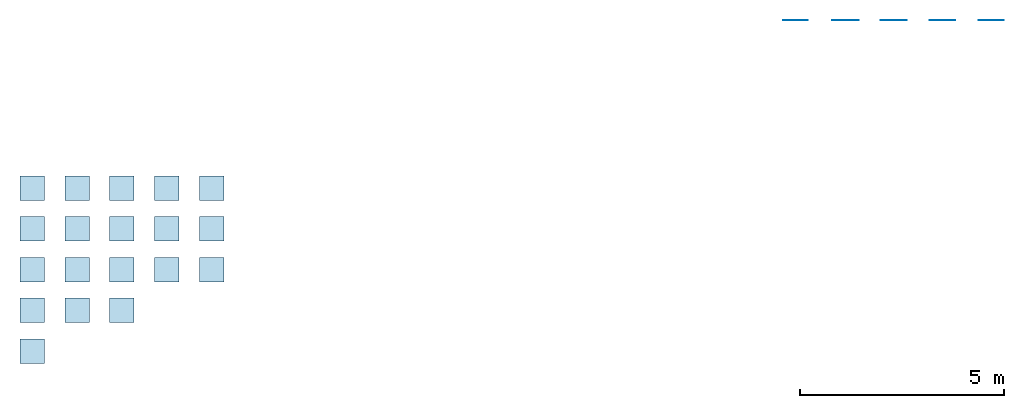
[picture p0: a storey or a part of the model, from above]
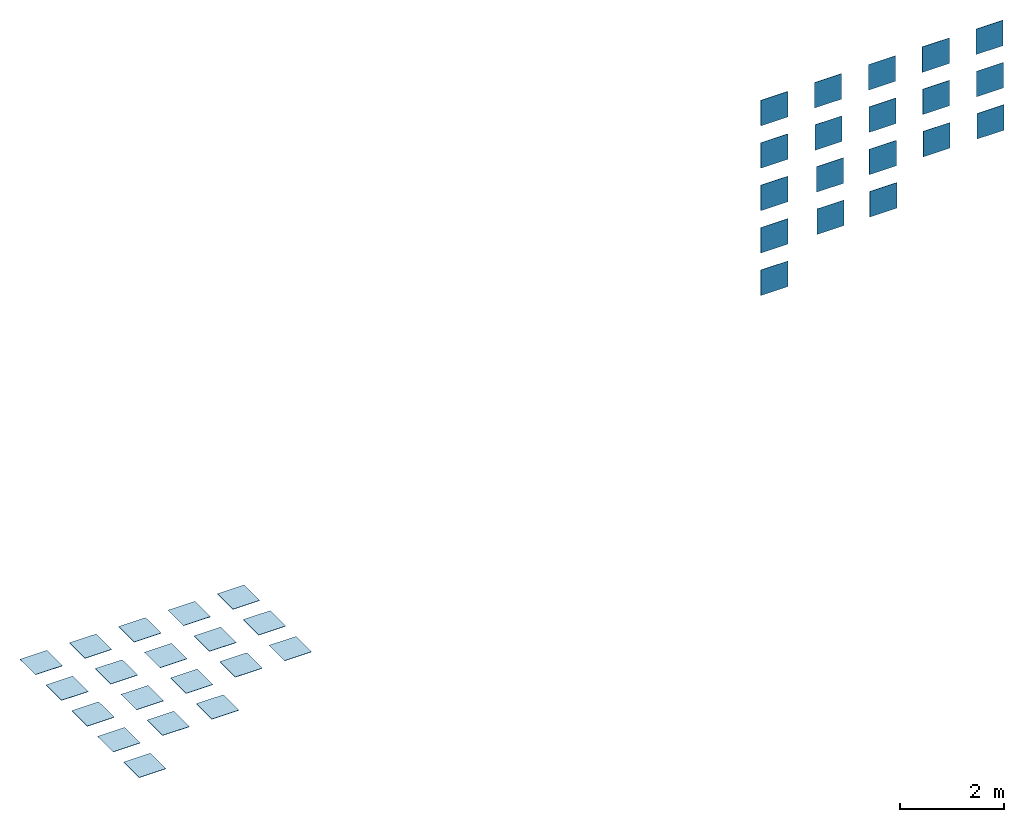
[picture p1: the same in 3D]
Properties of the parts of a building model (IFC2X3)

# File
Description: ViewDefinition [CoordinationView_V2.0]
File name: Número de proyecto
Time: 2017-10-19T12:50:17
Written by: The EXPRESS Data Manager Version 5.02.0100.07 : 28 Aug 2013
Made in: 20160225_1515(x64) - Exporter 17.0.416.0 - Alternate UI 17.12.14.0
Comment: STEP Physical File produced by: The EXPRESS Data Manager Version 5.02.0100.07 : 28 Aug 2013 * Module: EDMstepFileFactory/EDMstandAlone * Creation date: Thu Oct 19 12:50:17 2017 * Host: REVIT * Database: C:\Users\corte\AppData\Local\Temp\{6D7266B0-AC30-462C-87F8-137BDFE23D05}\ifc * Database version: 5507 * Database creation date: Thu Oct 19 12:50:14 2017 * Schema: IFC2X3 * Model: DataRepository.ifc * Model creation date: Thu Oct 19 12:50:14 2017 * Header model: DataRepository.ifc_HeaderModel * Header model creation date: Thu Oct 19 12:50:14 2017 * EDMuser: sdai-user * EDMgroup: sdai-group * License ID and type: 5605 : Permanent license. Expiry date: * EDMstepFileFactory options: 020000

# IfcProject, Número de proyecto
LongName: Nombre de proyecto; Phase: Estado de proyecto

# IfcSite, Default
RefLatitude: 40, 25, 0, 86975; RefLongitude: -3, -42, -1, -243858; RefElevation: 0 m

# IfcBuilding
Pset_BuildingCommon - NumberOfStoreys: 1

# IfcBuildingStorey, MAORI FLOOR TILES
LongName: MAORI FLOOR TILES; Elevation: 0 m

# IfcSlab: Suelo:VIVES BANNA 20x20, Suelo:VIVES BANNA 20x20:205106
In: MAORI FLOOR TILES
PredefinedType: FLOOR; Material: VIVES BANNA 20x20 0.008 m
Pset_SlabCommon - IsExternal: no; LoadBearing: yes; PitchAngle: 0 deg; Reference: VIVES BANNA 20x20; ThermalTransmittance: 187.5 kg/K/s3
Pset_ManufacturerTypeInformation - Manufacturer: VIVES Azulejos y Gres S.A.

# IfcSlab: Suelo:VIVES GOROKA CIELO 20x20, Suelo:VIVES GOROKA CIELO 20x20:204406
In: MAORI FLOOR TILES
PredefinedType: FLOOR; Material: VIVES GOROKA CIELO 20x20 0.008 m
Pset_SlabCommon - IsExternal: no; LoadBearing: yes; PitchAngle: 0 deg; Reference: VIVES GOROKA CIELO 20x20; ThermalTransmittance: 187.5 kg/K/s3
Pset_ManufacturerTypeInformation - Manufacturer: VIVES Azulejos y Gres S.A.

# IfcSlab: Suelo:VIVES GOROKA GRAFITO 20x20, Suelo:VIVES GOROKA GRAFITO 20x20:204430
In: MAORI FLOOR TILES
PredefinedType: FLOOR; Material: VIVES GOROKA GRAFITO 20x20 0.008 m
Pset_SlabCommon - IsExternal: no; LoadBearing: yes; PitchAngle: 0 deg; Reference: VIVES GOROKA GRAFITO 20x20; ThermalTransmittance: 187.5 kg/K/s3
Pset_ManufacturerTypeInformation - Manufacturer: VIVES Azulejos y Gres S.A.

# IfcSlab: Suelo:VIVES GOROKA GRIS 20x20, Suelo:VIVES GOROKA GRIS 20x20:204398
In: MAORI FLOOR TILES
PredefinedType: FLOOR; Material: VIVES GOROKA GRIS 20x20 0.008 m
Pset_SlabCommon - IsExternal: no; LoadBearing: yes; PitchAngle: 0 deg; Reference: VIVES GOROKA GRIS 20x20; ThermalTransmittance: 187.5 kg/K/s3
Pset_ManufacturerTypeInformation - Manufacturer: VIVES Azulejos y Gres S.A.

# IfcSlab: Suelo:VIVES GOROKA MUSGO 20x20, Suelo:VIVES GOROKA MUSGO 20x20:204414
In: MAORI FLOOR TILES
PredefinedType: FLOOR; Material: VIVES GOROKA MUSGO 20x20 0.008 m
Pset_SlabCommon - IsExternal: no; LoadBearing: yes; PitchAngle: 0 deg; Reference: VIVES GOROKA MUSGO 20x20; ThermalTransmittance: 187.5 kg/K/s3
Pset_ManufacturerTypeInformation - Manufacturer: VIVES Azulejos y Gres S.A.

# IfcSlab: Suelo:VIVES GOROKA OCRE 20x20, Suelo:VIVES GOROKA OCRE 20x20:204422
In: MAORI FLOOR TILES
PredefinedType: FLOOR; Material: VIVES GOROKA OCRE 20x20 0.008 m
Pset_SlabCommon - IsExternal: no; LoadBearing: yes; PitchAngle: 0 deg; Reference: VIVES GOROKA OCRE 20x20; ThermalTransmittance: 187.5 kg/K/s3
Pset_ManufacturerTypeInformation - Manufacturer: VIVES Azulejos y Gres S.A.

# IfcSlab: Suelo:VIVES HAMAR 20x20, Suelo:VIVES HAMAR 20x20:205114
In: MAORI FLOOR TILES
PredefinedType: FLOOR; Material: VIVES HAMAR 20x20 0.008 m
Pset_SlabCommon - IsExternal: no; LoadBearing: yes; PitchAngle: 0 deg; Reference: VIVES HAMAR 20x20; ThermalTransmittance: 187.5 kg/K/s3
Pset_ManufacturerTypeInformation - Manufacturer: VIVES Azulejos y Gres S.A.

# IfcSlab: Suelo:VIVES LADAKHI CIELO 20x20, Suelo:VIVES LADAKHI CIELO 20x20:204040
In: MAORI FLOOR TILES
PredefinedType: FLOOR; Material: VIVES LADAKHI CIELO 20x20 0.008 m
Pset_SlabCommon - IsExternal: no; LoadBearing: yes; PitchAngle: 0 deg; Reference: VIVES LADAKHI CIELO 20x20; ThermalTransmittance: 187.5 kg/K/s3
Pset_ManufacturerTypeInformation - Manufacturer: VIVES Azulejos y Gres S.A.

# IfcSlab: Suelo:VIVES LADAKHI GRAFITO 20x20, Suelo:VIVES LADAKHI GRAFITO 20x20:204232
In: MAORI FLOOR TILES
PredefinedType: FLOOR; Material: VIVES LADAKHI GRAFITO 20x20 0.008 m
Pset_SlabCommon - IsExternal: no; LoadBearing: yes; PitchAngle: 0 deg; Reference: VIVES LADAKHI GRAFITO 20x20; ThermalTransmittance: 187.5 kg/K/s3
Pset_ManufacturerTypeInformation - Manufacturer: VIVES Azulejos y Gres S.A.

# IfcSlab: Suelo:VIVES LADAKHI GRIS 20x20, Suelo:VIVES LADAKHI GRIS 20x20:189750
In: MAORI FLOOR TILES
PredefinedType: FLOOR; Material: VIVES LADAKHI GRIS 20x20 0.008 m
Pset_SlabCommon - Reference: VIVES LADAKHI GRIS 20x20; IsExternal: no; LoadBearing: yes; ThermalTransmittance: 187.5 kg/K/s3; PitchAngle: 0 deg
Pset_ManufacturerTypeInformation - Manufacturer: VIVES Azulejos y Gres S.A.

# IfcSlab: Suelo:VIVES LADAKHI MUSGO 20x20, Suelo:VIVES LADAKHI MUSGO 20x20:204104
In: MAORI FLOOR TILES
PredefinedType: FLOOR; Material: VIVES LADAKHI MUSGO 20x20 0.008 m
Pset_SlabCommon - IsExternal: no; LoadBearing: yes; PitchAngle: 0 deg; Reference: VIVES LADAKHI MUSGO 20x20; ThermalTransmittance: 187.5 kg/K/s3
Pset_ManufacturerTypeInformation - Manufacturer: VIVES Azulejos y Gres S.A.

# IfcSlab: Suelo:VIVES LADAKHI OCRE 20x20, Suelo:VIVES LADAKHI OCRE 20x20:204168
In: MAORI FLOOR TILES
PredefinedType: FLOOR; Material: VIVES LADAKHI OCRE 20x20 0.008 m
Pset_SlabCommon - IsExternal: no; LoadBearing: yes; PitchAngle: 0 deg; Reference: VIVES LADAKHI OCRE 20x20; ThermalTransmittance: 187.5 kg/K/s3
Pset_ManufacturerTypeInformation - Manufacturer: VIVES Azulejos y Gres S.A.

# IfcSlab: Suelo:VIVES TIEBELE 20x20, Suelo:VIVES TIEBELE 20x20:205297
In: MAORI FLOOR TILES
PredefinedType: FLOOR; Material: VIVES TIEBELE 20x20 0.008 m
Pset_SlabCommon - IsExternal: no; LoadBearing: yes; PitchAngle: 0 deg; Reference: VIVES TIEBELE 20x20; ThermalTransmittance: 187.5 kg/K/s3
Pset_ManufacturerTypeInformation - Manufacturer: VIVES Azulejos y Gres S.A.

# IfcSlab: Suelo:VIVES VANUATU 20x20, Suelo:VIVES VANUATU 20x20:205122
In: MAORI FLOOR TILES
PredefinedType: FLOOR; Material: VIVES VANUATU 20x20 0.008 m
Pset_SlabCommon - IsExternal: no; LoadBearing: yes; PitchAngle: 0 deg; Reference: VIVES VANUATU 20x20; ThermalTransmittance: 187.5 kg/K/s3
Pset_ManufacturerTypeInformation - Manufacturer: VIVES Azulejos y Gres S.A.

# IfcSlab: Suelo:VIVES VODEVIL ANTRACITA 20x20, Suelo:VIVES VODEVIL ANTRACITA 20x20:204714
In: MAORI FLOOR TILES
PredefinedType: FLOOR; Material: VIVES VODEVIL ANTRACITA 20x20 0.008 m
Pset_SlabCommon - IsExternal: no; LoadBearing: yes; PitchAngle: 0 deg; Reference: VIVES VODEVIL ANTRACITA 20x20; ThermalTransmittance: 187.5 kg/K/s3
Pset_ManufacturerTypeInformation - Manufacturer: VIVES Azulejos y Gres S.A.

# IfcSlab: Suelo:VIVES VODEVIL BEIGE 20x20, Suelo:VIVES VODEVIL BEIGE 20x20:204706
In: MAORI FLOOR TILES
PredefinedType: FLOOR; Material: VIVES VODEVIL BEIGE 20x20 0.008 m
Pset_SlabCommon - IsExternal: no; LoadBearing: yes; PitchAngle: 0 deg; Reference: VIVES VODEVIL BEIGE 20x20; ThermalTransmittance: 187.5 kg/K/s3
Pset_ManufacturerTypeInformation - Manufacturer: VIVES Azulejos y Gres S.A.

# IfcSlab: Suelo:VIVES VODEVIL HUMO 20x20, Suelo:VIVES VODEVIL HUMO 20x20:204682
In: MAORI FLOOR TILES
PredefinedType: FLOOR; Material: VIVES VODEVIL HUMO 20x20 0.008 m
Pset_SlabCommon - IsExternal: no; LoadBearing: yes; PitchAngle: 0 deg; Reference: VIVES VODEVIL HUMO 20x20; ThermalTransmittance: 187.5 kg/K/s3
Pset_ManufacturerTypeInformation - Manufacturer: VIVES Azulejos y Gres S.A.

# IfcSlab: Suelo:VIVES VODEVIL NUBE 20x20, Suelo:VIVES VODEVIL NUBE 20x20:204690
In: MAORI FLOOR TILES
PredefinedType: FLOOR; Material: VIVES VODEVIL NUBE 20x20 0.008 m
Pset_SlabCommon - IsExternal: no; LoadBearing: yes; PitchAngle: 0 deg; Reference: VIVES VODEVIL NUBE 20x20; ThermalTransmittance: 187.5 kg/K/s3
Pset_ManufacturerTypeInformation - Manufacturer: VIVES Azulejos y Gres S.A.

# IfcSlab: Suelo:VIVES VODEVIL OLIVA 20x20, Suelo:VIVES VODEVIL OLIVA 20x20:204698
In: MAORI FLOOR TILES
PredefinedType: FLOOR; Material: VIVES VODEVIL OLIVA 20x20 0.008 m
Pset_SlabCommon - IsExternal: no; LoadBearing: yes; PitchAngle: 0 deg; Reference: VIVES VODEVIL OLIVA 20x20; ThermalTransmittance: 187.5 kg/K/s3
Pset_ManufacturerTypeInformation - Manufacturer: VIVES Azulejos y Gres S.A.

# IfcWallStandardCase: Muro básico:VIVES BANNA 20x20, Muro básico:VIVES BANNA 20x20:203529
In: MAORI FLOOR TILES
Type - PredefinedType: STANDARD; Material: VIVES BANNA 20x20 0.008 m
Pset_WallCommon - IsExternal: no; LoadBearing: no; ExtendToStructure: no; Reference: VIVES BANNA 20x20; ThermalTransmittance: 187.5 kg/K/s3
Pset_ManufacturerTypeInformation - Manufacturer: VIVES Azulejos y Gres S.A.

# IfcWallStandardCase: Muro básico:VIVES GOROKA CIELO 20x20, Muro básico:VIVES GOROKA CIELO 20x20:202528
In: MAORI FLOOR TILES
Type - PredefinedType: STANDARD; Material: VIVES GOROKA CIELO 20x20 0.008 m
Pset_WallCommon - IsExternal: no; LoadBearing: no; ExtendToStructure: no; Reference: VIVES GOROKA CIELO 20x20; ThermalTransmittance: 187.5 kg/K/s3
Pset_ManufacturerTypeInformation - Manufacturer: VIVES Azulejos y Gres S.A.

# IfcWallStandardCase: Muro básico:VIVES GOROKA GRAFITO 20x20, Muro básico:VIVES GOROKA GRAFITO 20x20:202826
In: MAORI FLOOR TILES
Type - PredefinedType: STANDARD; Material: VIVES GOROKA GRAFITO 20x20 0.008 m
Pset_WallCommon - IsExternal: no; LoadBearing: no; ExtendToStructure: no; Reference: VIVES GOROKA GRAFITO 20x20; ThermalTransmittance: 187.5 kg/K/s3
Pset_ManufacturerTypeInformation - Manufacturer: VIVES Azulejos y Gres S.A.

# IfcWallStandardCase: Muro básico:VIVES GOROKA GRIS 20x20, Muro básico:VIVES GOROKA GRIS 20x20:202410
In: MAORI FLOOR TILES
Type - PredefinedType: STANDARD; Material: VIVES GOROKA GRIS 20x20 0.008 m
Pset_WallCommon - IsExternal: no; LoadBearing: no; ExtendToStructure: no; Reference: VIVES GOROKA GRIS 20x20; ThermalTransmittance: 187.5 kg/K/s3
Pset_ManufacturerTypeInformation - Manufacturer: VIVES Azulejos y Gres S.A.

# IfcWallStandardCase: Muro básico:VIVES GOROKA MUSGO 20x20, Muro básico:VIVES GOROKA MUSGO 20x20:202628
In: MAORI FLOOR TILES
Type - PredefinedType: STANDARD; Material: VIVES GOROKA MUSGO 20x20 0.008 m
Pset_WallCommon - IsExternal: no; LoadBearing: no; ExtendToStructure: no; Reference: VIVES GOROKA MUSGO 20x20; ThermalTransmittance: 187.5 kg/K/s3
Pset_ManufacturerTypeInformation - Manufacturer: VIVES Azulejos y Gres S.A.

# IfcWallStandardCase: Muro básico:VIVES GOROKA OCRE 20x20, Muro básico:VIVES GOROKA OCRE 20x20:202728
In: MAORI FLOOR TILES
Type - PredefinedType: STANDARD; Material: VIVES GOROKA OCRE 20x20 0.008 m
Pset_WallCommon - IsExternal: no; LoadBearing: no; ExtendToStructure: no; Reference: VIVES GOROKA OCRE 20x20; ThermalTransmittance: 187.5 kg/K/s3
Pset_ManufacturerTypeInformation - Manufacturer: VIVES Azulejos y Gres S.A.

# IfcWallStandardCase: Muro básico:VIVES HAMAR 20x20, Muro básico:VIVES HAMAR 20x20:203689
In: MAORI FLOOR TILES
Type - PredefinedType: STANDARD; Material: VIVES HAMAR 20x20 0.008 m
Pset_WallCommon - IsExternal: no; LoadBearing: no; ExtendToStructure: no; Reference: VIVES HAMAR 20x20; ThermalTransmittance: 187.5 kg/K/s3
Pset_ManufacturerTypeInformation - Manufacturer: VIVES Azulejos y Gres S.A.

# IfcWallStandardCase: Muro básico:VIVES LADAKHI CIELO 20x20, Muro básico:VIVES LADAKHI CIELO 20x20:201892
In: MAORI FLOOR TILES
Type - PredefinedType: STANDARD; Material: VIVES LADAKHI CIELO 20x20 0.008 m
Pset_WallCommon - IsExternal: no; LoadBearing: no; ExtendToStructure: no; Reference: VIVES LADAKHI CIELO 20x20; ThermalTransmittance: 187.5 kg/K/s3
Pset_ManufacturerTypeInformation - Manufacturer: VIVES Azulejos y Gres S.A.

# IfcWallStandardCase: Muro básico:VIVES LADAKHI GRAFITO 20x20, Muro básico:VIVES LADAKHI GRAFITO 20x20:202248
In: MAORI FLOOR TILES
Type - PredefinedType: STANDARD; Material: VIVES LADAKHI GRAFITO 20x20 0.008 m
Pset_WallCommon - IsExternal: no; LoadBearing: no; ExtendToStructure: no; Reference: VIVES LADAKHI GRAFITO 20x20; ThermalTransmittance: 187.5 kg/K/s3
Pset_ManufacturerTypeInformation - Manufacturer: VIVES Azulejos y Gres S.A.

# IfcWallStandardCase: Muro básico:VIVES LADAKHI GRIS 20x20, Muro básico:VIVES LADAKHI GRIS 20x20:190692
In: MAORI FLOOR TILES
Type - PredefinedType: STANDARD; Material: VIVES LADAKHI GRIS 20x20 0.008 m
Pset_WallCommon - Reference: VIVES LADAKHI GRIS 20x20; IsExternal: no; LoadBearing: no; ExtendToStructure: no; ThermalTransmittance: 187.5 kg/K/s3
Pset_ManufacturerTypeInformation - Manufacturer: VIVES Azulejos y Gres S.A.

# IfcWallStandardCase: Muro básico:VIVES LADAKHI MUSGO 20x20, Muro básico:VIVES LADAKHI MUSGO 20x20:202000
In: MAORI FLOOR TILES
Type - PredefinedType: STANDARD; Material: VIVES LADAKHI MUSGO 20x20 0.008 m
Pset_WallCommon - IsExternal: no; LoadBearing: no; ExtendToStructure: no; Reference: VIVES LADAKHI MUSGO 20x20; ThermalTransmittance: 187.5 kg/K/s3
Pset_ManufacturerTypeInformation - Manufacturer: VIVES Azulejos y Gres S.A.

# IfcWallStandardCase: Muro básico:VIVES LADAKHI OCRE 20x20, Muro básico:VIVES LADAKHI OCRE 20x20:202138
In: MAORI FLOOR TILES
Type - PredefinedType: STANDARD; Material: VIVES LADAKHI OCRE 20x20 0.008 m
Pset_WallCommon - IsExternal: no; LoadBearing: no; ExtendToStructure: no; Reference: VIVES LADAKHI OCRE 20x20; ThermalTransmittance: 187.5 kg/K/s3
Pset_ManufacturerTypeInformation - Manufacturer: VIVES Azulejos y Gres S.A.

# IfcWallStandardCase: Muro básico:VIVES TIEBELE 20x20, Muro básico:VIVES TIEBELE 20x20:203908
In: MAORI FLOOR TILES
Type - PredefinedType: STANDARD; Material: VIVES TIEBELE 20x20 0.008 m
Pset_WallCommon - IsExternal: no; LoadBearing: no; ExtendToStructure: no; Reference: VIVES TIEBELE 20x20; ThermalTransmittance: 187.5 kg/K/s3
Pset_ManufacturerTypeInformation - Manufacturer: VIVES Azulejos y Gres S.A.

# IfcWallStandardCase: Muro básico:VIVES VANUATU 20x20, Muro básico:VIVES VANUATU 20x20:203810
In: MAORI FLOOR TILES
Type - PredefinedType: STANDARD; Material: VIVES VANUATU 20x20 0.008 m
Pset_WallCommon - IsExternal: no; LoadBearing: no; ExtendToStructure: no; Reference: VIVES VANUATU 20x20; ThermalTransmittance: 187.5 kg/K/s3
Pset_ManufacturerTypeInformation - Manufacturer: VIVES Azulejos y Gres S.A.

# IfcWallStandardCase: Muro básico:VIVES VODEVIL ANTRACITA 20x20, Muro básico:VIVES VODEVIL ANTRACITA 20x20:203431
In: MAORI FLOOR TILES
Type - PredefinedType: STANDARD; Material: VIVES VODEVIL ANTRACITA 20x20 0.008 m
Pset_WallCommon - IsExternal: no; LoadBearing: no; ExtendToStructure: no; Reference: VIVES VODEVIL ANTRACITA 20x20; ThermalTransmittance: 187.5 kg/K/s3
Pset_ManufacturerTypeInformation - Manufacturer: VIVES Azulejos y Gres S.A.

# IfcWallStandardCase: Muro básico:VIVES VODEVIL BEIGE 20x20, Muro básico:VIVES VODEVIL BEIGE 20x20:203319
In: MAORI FLOOR TILES
Type - PredefinedType: STANDARD; Material: VIVES VODEVIL BEIGE 20x20 0.008 m
Pset_WallCommon - IsExternal: no; LoadBearing: no; ExtendToStructure: no; Reference: VIVES VODEVIL BEIGE 20x20; ThermalTransmittance: 187.5 kg/K/s3
Pset_ManufacturerTypeInformation - Manufacturer: VIVES Azulejos y Gres S.A.

# IfcWallStandardCase: Muro básico:VIVES VODEVIL HUMO 20x20, Muro básico:VIVES VODEVIL HUMO 20x20:202967
In: MAORI FLOOR TILES
Type - PredefinedType: STANDARD; Material: VIVES VODEVIL HUMO 20x20 0.008 m
Pset_WallCommon - IsExternal: no; LoadBearing: no; ExtendToStructure: no; Reference: VIVES VODEVIL HUMO 20x20; ThermalTransmittance: 187.5 kg/K/s3
Pset_ManufacturerTypeInformation - Manufacturer: VIVES Azulejos y Gres S.A.

# IfcWallStandardCase: Muro básico:VIVES VODEVIL NUBE 20x20, Muro básico:VIVES VODEVIL NUBE 20x20:203095
In: MAORI FLOOR TILES
Type - PredefinedType: STANDARD; Material: VIVES VODEVIL NUBE 20x20 0.008 m
Pset_WallCommon - IsExternal: no; LoadBearing: no; ExtendToStructure: no; Reference: VIVES VODEVIL NUBE 20x20; ThermalTransmittance: 187.5 kg/K/s3
Pset_ManufacturerTypeInformation - Manufacturer: VIVES Azulejos y Gres S.A.

# IfcWallStandardCase: Muro básico:VIVES VODEVIL OLIVA 20x20, Muro básico:VIVES VODEVIL OLIVA 20x20:203221
In: MAORI FLOOR TILES
Type - PredefinedType: STANDARD; Material: VIVES VODEVIL OLIVA 20x20 0.008 m
Pset_WallCommon - IsExternal: no; LoadBearing: no; ExtendToStructure: no; Reference: VIVES VODEVIL OLIVA 20x20; ThermalTransmittance: 187.5 kg/K/s3
Pset_ManufacturerTypeInformation - Manufacturer: VIVES Azulejos y Gres S.A.
